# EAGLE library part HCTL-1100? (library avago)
General Purpose Motion Control ICs Source: AVAGO TECHNOLOGIES .. 5988-5896EN.pdf

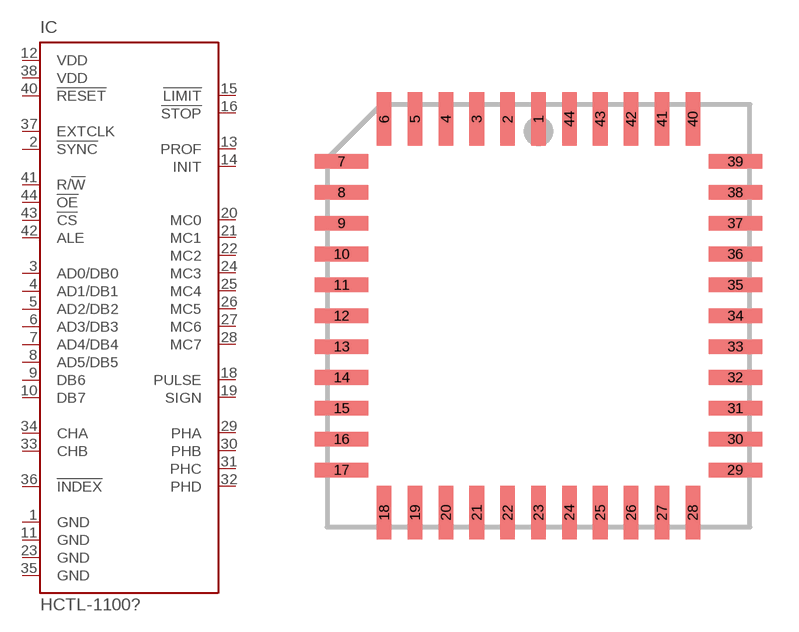
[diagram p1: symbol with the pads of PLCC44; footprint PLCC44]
Designator prefix IC

## HCTL-1100PLC (MF: AGILENT TECHNOLOGIES; MPN: HCTL-1100#PLC; OC_FARNELL: unknown; OC_NEWARK: 17M9299)  [PLCC44]
1  GND  pwr
2  !SYNC  in
3  AD0/DB0
4  AD1/DB1
5  AD2/DB2
6  AD3/DB3
7  AD4/DB4
8  AD5/DB5
9  DB6
10  DB7
11  GND  pwr
12  VDD  pwr
13  PROF  out
14  INIT  out
15  !LIMIT  in
16  !STOP  in
18  PULSE  out
19  SIGN  out
20  MC0  out
21  MC1  out
22  MC2  out
23  GND  pwr
24  MC3  out
25  MC4  out
26  MC5  out
27  MC6  out
28  MC7  out
29  PHA  out
30  PHB  out
31  PHC  out
32  PHD  out
33  CHB  in
34  CHA  in
35  GND  pwr
36  !INDEX  in
37  EXTCLK  in
38  VDD  pwr
40  !RESET  in
41  R/!W  in
42  ALE  in
43  !CS  in
44  !OE  in

## Footprint PLCC44 (pad centres in mm)
PLASTIC LEADED CHIP CARRIER square
smd 0.6 x 2.2: 1 0,8.1; 2 -1.27,8.1; 3 -2.54,8.1; 4 -3.81,8.1; 5 -5.08,8.1; 6 -6.35,8.1; 18 -6.35,-8.1; 19 -5.08,-8.1; 20 -3.81,-8.1; 21 -2.54,-8.1; 22 -1.27,-8.1; 23 0,-8.1; 24 1.27,-8.1; 25 2.54,-8.1; 26 3.81,-8.1; 27 5.08,-8.1; 28 6.35,-8.1; 40 6.35,8.1; 41 5.08,8.1; 42 3.81,8.1; 43 2.54,8.1; 44 1.27,8.1
smd 2.2 x 0.6: 7 -8.1,6.35; 8 -8.1,5.08; 9 -8.1,3.81; 10 -8.1,2.54; 11 -8.1,1.27; 12 -8.1,0; 13 -8.1,-1.27; 14 -8.1,-2.54; 15 -8.1,-3.81; 16 -8.1,-5.08; 17 -8.1,-6.35; 29 8.1,-6.35; 30 8.1,-5.08; 31 8.1,-3.81; 32 8.1,-2.54; 33 8.1,-1.27; 34 8.1,0; 35 8.1,1.27; 36 8.1,2.54; 37 8.1,3.81; 38 8.1,5.08; 39 8.1,6.35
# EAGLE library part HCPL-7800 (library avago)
Isolation Amplifer Source: http://www.avagotech.com/docs/AV02-0410EN

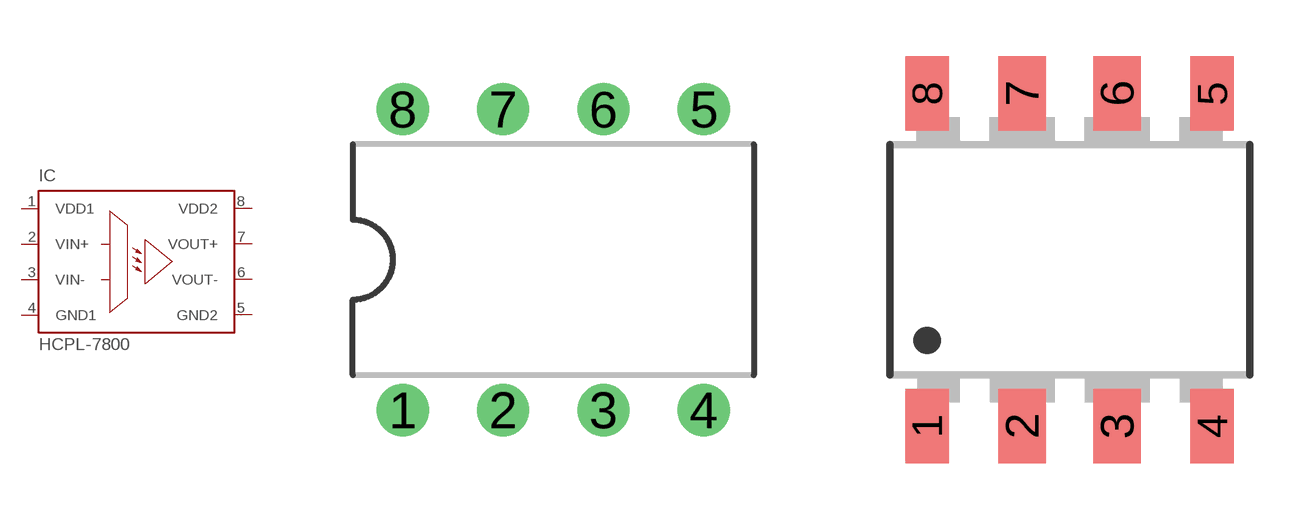
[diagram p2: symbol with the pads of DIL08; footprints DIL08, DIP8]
Designator prefix IC

## HCPL-7800 (MPN: HCPL-7800A#500; OC_FARNELL: 459446; OC_NEWARK: 05M6395)  [DIL08]
1  VDD1  pwr
2  VIN+  pwr
3  VIN-  pwr
4  GND1  pwr
5  GND2  pwr
6  VOUT-  pwr
7  VOUT+  pwr
8  VDD2  pwr

## HCPL-7800A (MF: AGILENT TECHNOLOGIES; MPN: HCPL-7800A-000E; OC_FARNELL: 8550026; OC_NEWARK: 88H7847)  [DIP8]
Pads as for DIL08

## Footprint DIL08 (pad centres in mm)
Dual In Line Package
drill 0.813 pad 1.3: 1 -3.81,-3.81; 2 -1.27,-3.81; 3 1.27,-3.81; 4 3.81,-3.81; 5 3.81,3.81; 6 1.27,3.81; 7 -1.27,3.81; 8 -3.81,3.81

## Footprint DIP8 (pad centres in mm)
SMD DIL08 Gull Wing Surface Mount Optioon 300 Source: http://www.avagotech.com/docs/AV02-0410EN
smd 1.16 x 2: 1 -3.81,-4.45; 4 3.81,-4.45; 5 3.81,4.45; 8 -3.81,4.45
smd 1.27 x 2: 2 -1.27,-4.45; 3 1.27,-4.45; 6 1.27,4.45; 7 -1.27,4.45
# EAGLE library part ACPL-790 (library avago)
Precision Isolation Amplifiers Source: Data sheet

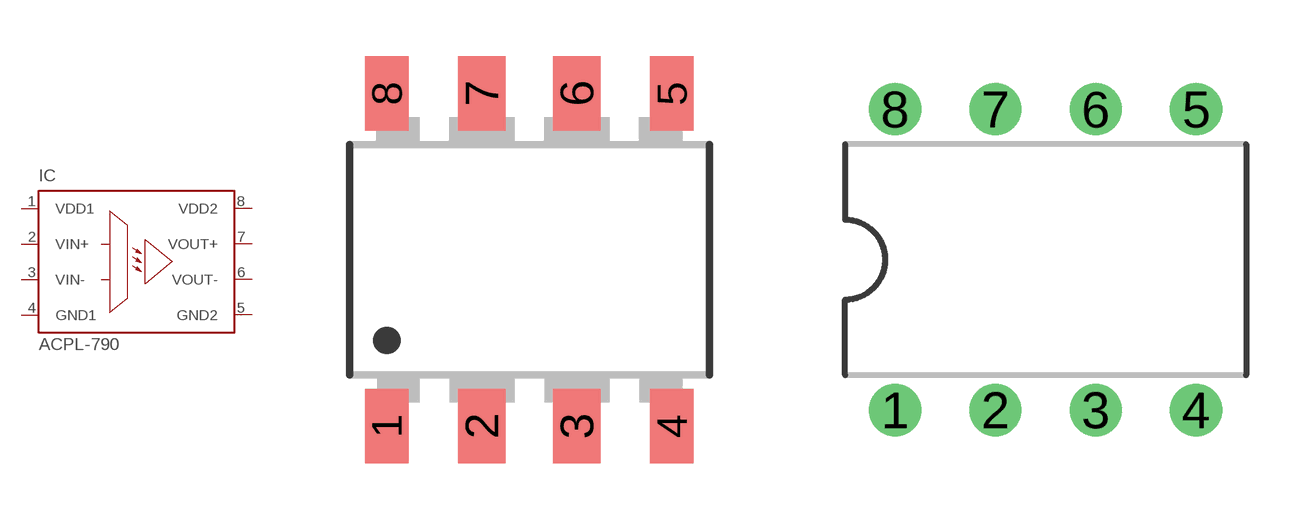
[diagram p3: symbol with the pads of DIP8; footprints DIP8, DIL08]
Designator prefix IC

## ACPL-7900, ACPL-790A  [DIP8]
1  VDD1  pwr
2  VIN+  pwr
3  VIN-  pwr
4  GND1  pwr
5  GND2  pwr
6  VOUT-  pwr
7  VOUT+  pwr
8  VDD2  pwr

## ACPL-790B  [DIL08]
Pads as for DIP8

## Footprint DIP8 (pad centres in mm)
SMD DIL08 Gull Wing Surface Mount Optioon 300 Source: http://www.avagotech.com/docs/AV02-0410EN
smd 1.16 x 2: 1 -3.81,-4.45; 4 3.81,-4.45; 5 3.81,4.45; 8 -3.81,4.45
smd 1.27 x 2: 2 -1.27,-4.45; 3 1.27,-4.45; 6 1.27,4.45; 7 -1.27,4.45

## Footprint DIL08 (pad centres in mm)
Dual In Line Package
drill 0.813 pad 1.3: 1 -3.81,-3.81; 2 -1.27,-3.81; 3 1.27,-3.81; 4 3.81,-3.81; 5 3.81,3.81; 6 1.27,3.81; 7 -1.27,3.81; 8 -3.81,3.81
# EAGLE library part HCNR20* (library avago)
High-Linearity Analog Optocouplers Source: AV02-0886EN+DS+HCNR200+10Dec2011.pdf

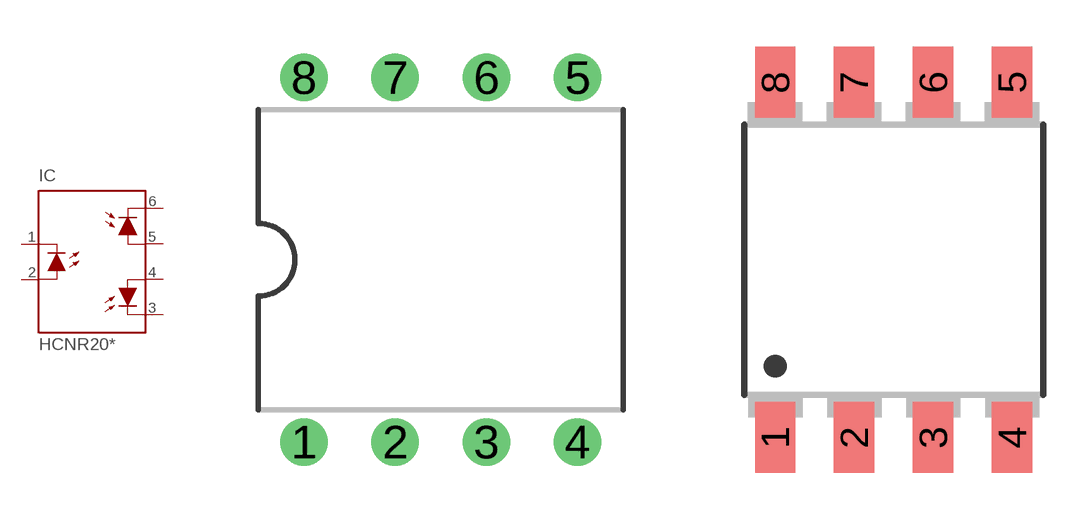
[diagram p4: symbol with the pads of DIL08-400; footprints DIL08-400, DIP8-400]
Designator prefix IC

## HCNR200, HCNR201  [DIL08-400]
1  C  pas
2  A  pas
3  C1  pas
4  A1  pas
5  A2  pas
6  C2  pas

## HCNR200-300E, HCNR201-300E  [DIP8-400]
Pads as for DIL08-400

## Footprint DIL08-400 (pad centres in mm)
Dual In Line Package 400 mil Widebody DIP 8 Source: AV02-0886EN+DS+HCNR200+10Dec2011-1.pdf
drill 0.813 pad 1.3: 1 -3.81,-5.08; 2 -1.27,-5.08; 3 1.27,-5.08; 4 3.81,-5.08; 5 3.81,5.08; 6 1.27,5.08; 7 -1.27,5.08; 8 -3.81,5.08

## Footprint DIP8-400 (pad centres in mm)
Dual In Line Package Gull Wing Surface Mount Option 400 mil Widebody DIP 8 Source: AV02-0886EN+DS+HCNR200+10Dec2011-1.pdf
smd 1.3 x 2.29: 1 -3.81,-5.72; 2 -1.27,-5.72; 3 1.27,-5.72; 4 3.81,-5.72; 5 3.81,5.72; 6 1.27,5.72; 7 -1.27,5.72; 8 -3.81,5.72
